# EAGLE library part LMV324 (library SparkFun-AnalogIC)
Jellybean quad op-amp

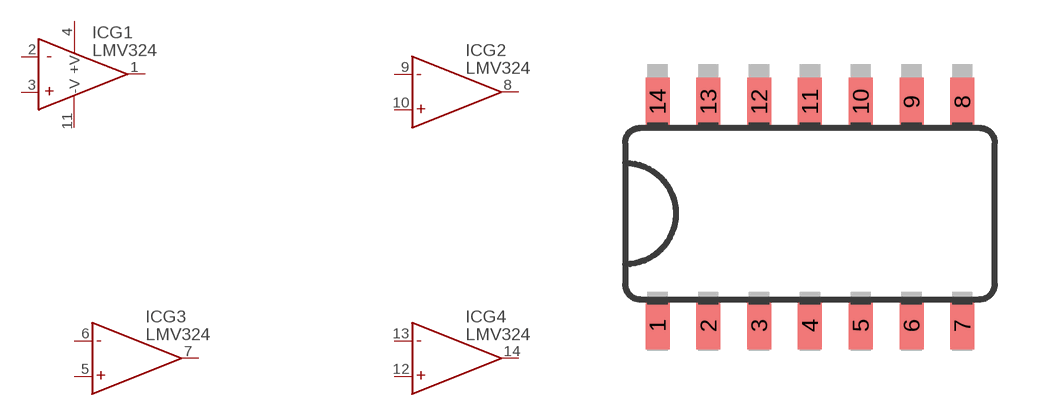
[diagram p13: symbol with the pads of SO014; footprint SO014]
Designator prefix IC; gates G1=LMV324 G3=LMV324_2 G2=LMV324_2 G4=LMV324_2

## LMV324 (PROD_ID: IC-08227; VALUE: LMV324)  [SO014]
1  G1:OUT  out
2  G1:-IN  in
3  G1:+IN  in
4  G1:+V  pwr
5  G3:+IN  in
6  G3:-IN  in
7  G3:OUT  out
8  G2:OUT  out
9  G2:-IN  in
10  G2:+IN  in
11  G1:-V  pwr
12  G4:+IN  in
13  G4:-IN  in
14  G4:OUT  out

## Footprint SO014 (pad centres in mm)
smd 0.6 x 1.2: 1 -3.175,-2.8; 2 -1.905,-2.8; 3 -0.635,-2.8; 4 0.635,-2.8; 5 1.905,-2.8; 6 3.175,-2.8; 7 4.445,-2.8; 8 4.445,2.8; 9 3.175,2.8; 10 1.905,2.8; 11 0.635,2.8; 12 -0.635,2.8; 13 -1.905,2.8; 14 -3.175,2.8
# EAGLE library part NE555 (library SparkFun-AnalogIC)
General purpose bipolar Timer

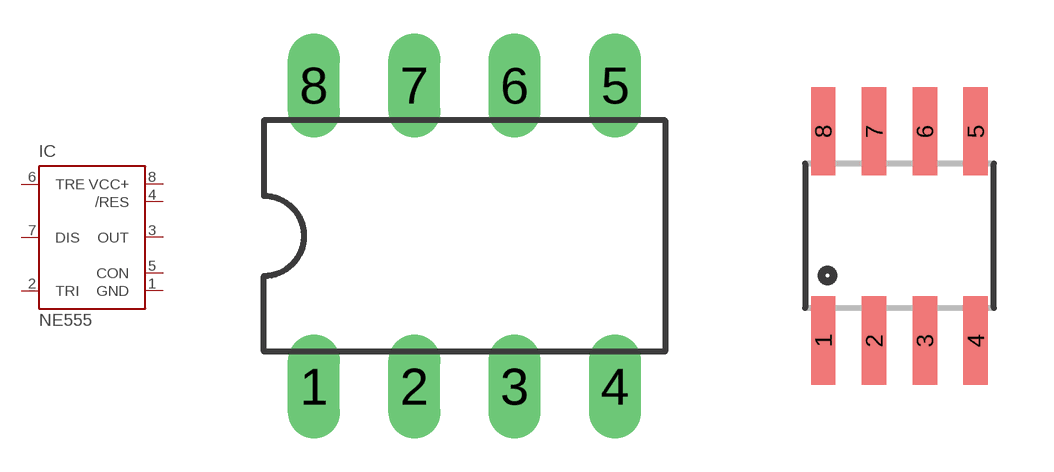
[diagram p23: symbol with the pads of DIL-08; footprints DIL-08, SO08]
Designator prefix IC

## NE555P (MF: Arrow Electronics; MPN: NE555N; OC_FARNELL: 1467742; OC_NEWARK: 89K1486)  [DIL-08]
1  GND  pwr
2  TRI  in
3  OUT  out
4  /RES  in
5  CON  in
6  TRE  in
7  DIS  in
8  VCC+  pwr

## NE555D  [SO08]
Pads as for DIL-08

## NE555KIT (PROD_ID: IC-11930)  [DIP08-KIT]
Pads as for DIL-08

## Footprint DIL-08 (pad centres in mm)
Dual In Line Package
drill 0.813 long: 1 -3.81,-3.81; 2 -1.27,-3.81; 3 1.27,-3.81; 4 3.81,-3.81; 5 3.81,3.81; 6 1.27,3.81; 7 -1.27,3.81; 8 -3.81,3.81

## Footprint SO08 (pad centres in mm)
Small Outline Package Fits JEDEC packages (narrow SOIC-8)
smd 0.61 x 2.21: 1 -1.905,-2.616; 2 -0.635,-2.616; 3 0.635,-2.616; 4 1.905,-2.616; 5 1.905,2.616; 6 0.635,2.616; 7 -0.635,2.616; 8 -1.905,2.616

## Footprint DIP08-KIT (pad centres in mm)
drill 0.813 pad 1.727: 1 -3.81,-4.191; 2 -1.27,-4.191; 3 1.27,-4.191; 4 3.81,-4.191; 5 3.81,4.191; 6 1.27,4.191; 7 -1.27,4.191; 8 -3.81,4.191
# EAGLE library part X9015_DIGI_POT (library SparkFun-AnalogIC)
Digital pot- up/down/increment control only

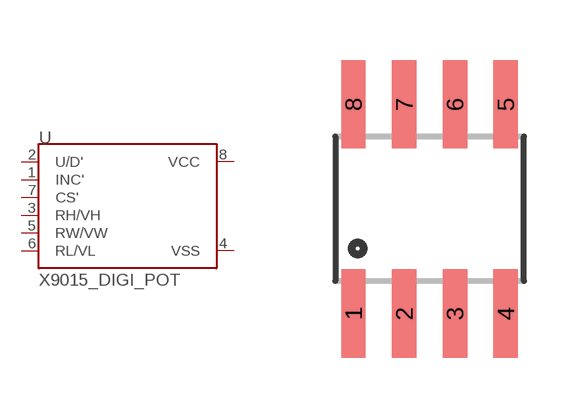
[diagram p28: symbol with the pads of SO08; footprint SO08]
Designator prefix -

## X9015_DIGI_POTS  [SO08]
1  INC'
2  U/D'
3  RH/VH
4  VSS  pwr
5  RW/VW
6  RL/VL
7  CS'
8  VCC  pwr

## Footprint SO08 (pad centres in mm)
Small Outline Package Fits JEDEC packages (narrow SOIC-8)
smd 0.61 x 2.21: 1 -1.905,-2.616; 2 -0.635,-2.616; 3 0.635,-2.616; 4 1.905,-2.616; 5 1.905,2.616; 6 0.635,2.616; 7 -0.635,2.616; 8 -1.905,2.616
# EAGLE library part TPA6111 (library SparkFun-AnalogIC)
TPA6111A2: Basic 150mW stereo headphone amplifier.

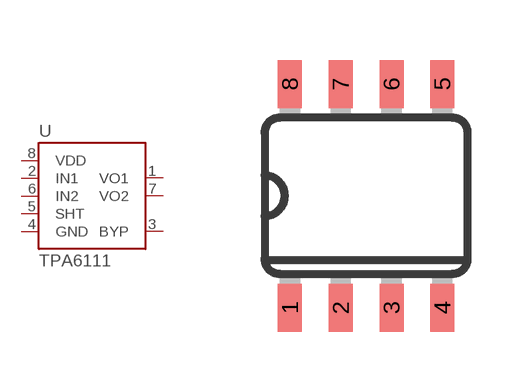
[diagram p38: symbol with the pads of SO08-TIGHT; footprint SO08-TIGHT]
Designator prefix U

## TPA6111SMD-T (PROD_ID: IC-10149)  [SO08-TIGHT]
1  VO1
2  IN1
3  BYP
4  GND
5  SHT
6  IN2
7  VO2
8  VDD

## Footprint SO08-TIGHT (pad centres in mm)
smd 0.6 x 1.2: 1 -1.905,-2.8; 2 -0.635,-2.8; 3 0.635,-2.8; 4 1.905,-2.8; 5 1.905,2.8; 6 0.635,2.8; 7 -0.635,2.8; 8 -1.905,2.8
